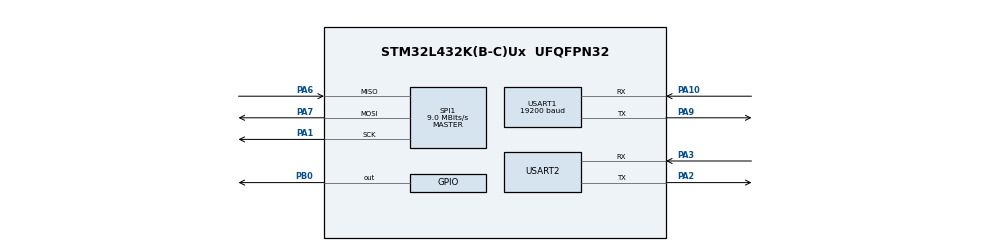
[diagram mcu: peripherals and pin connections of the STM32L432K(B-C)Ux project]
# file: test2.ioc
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FATFS._MAX_SS=4096
FATFS._USE_LFN=1
Mcu.Family=STM32L4
Mcu.Name=STM32L432K(B-C)Ux
Mcu.Package=UFQFPN32
NVIC.PriorityGroup=NVIC_PRIORITYGROUP_4
PA0.Mode=HSE-External-Clock-Source-for-LittleOrca
PA0.Signal=RCC_CK_IN
PA1.Mode=Full_Duplex_Master
PA1.Signal=SPI1_SCK
PA10.Mode=Asynchronous
PA10.Signal=USART1_RX
PA13\ (JTMS-SWDIO).Mode=Serial_Wire
PA13\ (JTMS-SWDIO).Signal=SYS_JTMS-SWDIO
PA14\ (JTCK-SWCLK).Mode=Serial_Wire
PA14\ (JTCK-SWCLK).Signal=SYS_JTCK-SWCLK
PA2.Mode=Asynchronous
PA2.Signal=USART2_TX
PA3.Mode=Asynchronous
PA3.Signal=USART2_RX
PA6.Mode=Full_Duplex_Master
PA6.Signal=SPI1_MISO
PA7.Mode=Full_Duplex_Master
PA7.Signal=SPI1_MOSI
PA9.Mode=Asynchronous
PA9.Signal=USART1_TX
PB0.Signal=GPIO_Output
ProjectManager.HeapSize=0x200
ProjectManager.StackSize=0x400
ProjectManager.TargetToolchain=MDK-ARM V5
RCC.ADCFreq_Value=32000000
RCC.AHBFreq_Value=72000000
RCC.APB1CLKDivider=RCC_HCLK_DIV2
RCC.APB1Freq_Value=36000000
RCC.APB1TimFreq_Value=72000000
RCC.APB2Freq_Value=72000000
RCC.APB2TimFreq_Value=72000000
RCC.CortexFreq_Value=72000000
RCC.HCLKFreq_Value=72000000
RCC.HSE_VALUE=8000000
RCC.HSI48_VALUE=48000000
RCC.HSI_VALUE=16000000
RCC.LSE_VALUE=32768
RCC.MSI_VALUE=4000000
RCC.PLLN=18
RCC.PLLSourceVirtual=RCC_PLLSOURCE_HSE
RCC.SYSCLKFreq_VALUE=72000000
RCC.SYSCLKSource=RCC_SYSCLKSOURCE_PLLCLK
RCC.USBFreq_Value=32000000
RCC.VCOOutputFreq_Value=144000000
SPI1.BaudRatePrescaler=SPI_BAUDRATEPRESCALER_8
SPI1.CalculateBaudRate=9.0 MBits/s
SPI1.Direction=SPI_DIRECTION_2LINES
SPI1.Mode=SPI_MODE_MASTER
SPI1.VirtualType=VM_MASTER
USART1.BaudRate=19200
USART1.VirtualMode-Asynchronous=VM_ASYNC
USART2.VirtualMode-Asynchronous=VM_ASYNC
VP_FATFS_VS_Generic.Mode=User_defined
board=custom

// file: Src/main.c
/* USER CODE BEGIN Header */
/**
  ******************************************************************************
  * @file           : main.c
  * @brief          : Main program body
  ******************************************************************************
  * @attention
  *
  * <h2><center>&copy; Copyright (c) 2020 STMicroelectronics.
  * All rights reserved.</center></h2>
  *
  * This software component is licensed by ST under BSD 3-Clause license,
  * the "License"; You may not use this file except in compliance with the
  * License. You may obtain a copy of the License at:
  *                        opensource.org/licenses/BSD-3-Clause
  *
  ******************************************************************************
  */
/* USER CODE END Header */

#include "main.h"
#include "fatfs.h"

/* USER CODE BEGIN Includes */
#include <stdio.h>
#include <stdlib.h>
#include <ctype.h>
#include <errno.h>
#include <string.h>
/* USER CODE END Includes */

SPI_HandleTypeDef hspi1;
UART_HandleTypeDef huart1;
UART_HandleTypeDef huart2;

void SystemClock_Config(void);
static void MX_GPIO_Init(void);
static void MX_SPI1_Init(void);
static void MX_USART1_UART_Init(void);
static void MX_USART2_UART_Init(void);

/* USER CODE BEGIN 0 */
FATFS fs;  // file system
FIL fil; // File
FILINFO fno;
FRESULT fresult;  // result
UINT br, bw;  // File read/write count
char buffer[1024];
char temp[1024];
char direction[1024];
int c;
int volatile turn = 0;
int volatile start;
int volatile Number_Of_States=0;
int volatile Number_Of_States_2=0;
int volatile Number_Of_Rotations=0;
int volatile Number_Of_Rotations_2=0;
int volatile previous_state;
int volatile previous_state_2;

/**** capacity related *****/
FATFS *pfs;
DWORD fre_clust;
uint32_t total, free_space;

void send_uart(char *string){
	uint8_t len = strlen(string);
	HAL_UART_Transmit(&huart2, (uint8_t *) string, len, HAL_MAX_DELAY);
}

int bufsize(char *buf){
	int i = 0;
	while (*buf++ != '\0') i++;
	return i;
}

void bufclear(void){
	for(int i = 0; i < 1024; i++){
		buffer[i] = '\0';
	}
}

/* USER CODE END 0 */

int main(void)
{

  /* MCU Configuration--------------------------------------------------------*/

  /* Reset of all peripherals, Initializes the Flash interface and the Systick. */
  HAL_Init();

  /* Configure the system clock */
  SystemClock_Config();

  /* Initialize all configured peripherals */
  MX_GPIO_Init();
  MX_SPI1_Init();
  MX_FATFS_Init();
	MX_USART1_UART_Init();
	MX_USART2_UART_Init();
  /* USER CODE BEGIN 2 */

	previous_state=HAL_GPIO_ReadPin(GPIOA,GPIO_PIN_11);
	int flag=1;
	int temp_directions_count=0;
	float volatile distance=0.0;

	HAL_GPIO_WritePin(GPIOB, GPIO_PIN_7, GPIO_PIN_RESET);

	previous_state=HAL_GPIO_ReadPin(GPIOA,GPIO_PIN_11);
	previous_state_2=HAL_GPIO_ReadPin(GPIOA,GPIO_PIN_0);

  fresult = f_mount(&fs, "/", 1);

	/* Check free space */
	f_getfree("", &fre_clust, &pfs);

	total = (uint32_t)((pfs->n_fatent - 2) * pfs->csize * 0.5);
	sprintf (buffer, "SD CARD Total Size: \t%lu\n\r",(unsigned long) total);
	send_uart(buffer);
	bufclear();

	free_space = (uint32_t)(fre_clust * pfs->csize * 0.5);
	sprintf (buffer, "SD CARD free space: \t%lu\n\r",(unsigned long) free_space);
	send_uart(buffer);
	bufclear();

	if(free_space < 100){
		send_uart("WARNING: not enough free space!\n\n\r");
	}

	fresult = f_open(&fil, "FILE1.TXT", FA_OPEN_ALWAYS | FA_READ | FA_WRITE);
	f_read(&fil, buffer, f_size(&fil), &br);
	send_uart(buffer);
	f_close(&fil);
	HAL_GPIO_WritePin(GPIOB, GPIO_PIN_7, GPIO_PIN_SET);

	int count = 0;

	for( int i = 0; i < sizeof(buffer); i++){
		if((buffer[i] != ' ') && (buffer[i] != '\n') && (buffer[i] != '\r')){
				temp[count] = buffer[i];
				count++;
		}
	}
	count = 0;

	int num;

	for( int i = 0; i < sizeof(temp); i++){
		if(temp[i] == 'F'){
			sscanf(&temp[i+1], "%d", &num);
			while(num > 0){
				direction[count] = temp[i];
				count++;
				num--;
			}
		}
		else if(temp[i] == 'B'){
			sscanf(&temp[i+1], "%d", &num);
			direction[count] = 'B';
			count++;
			num--;
			while(num > 0){
				direction[count] = 'F';
				count++;
				num--;
			}
		}
		else if(temp[i] == 'L' || temp[i] == 'R'){
			direction[count] = temp[i];
			count++;
		}
	}

	send_uart(direction);
	count = 0;
	turn = 1;
	HAL_GPIO_WritePin(GPIOB, GPIO_PIN_5, GPIO_PIN_SET);
  /* USER CODE END 2 */

  /* Infinite loop */
  /* USER CODE BEGIN WHILE */
  while (1)
  {
		uint8_t wheel[] = {0xC1, 0xC9, 0xC1, 0xC9,0xC0};
		uint8_t speed[] = {64, 32, 0};
		start = HAL_GPIO_ReadPin(GPIOA, GPIO_PIN_8);
		if(flag==1 && direction[temp_directions_count]=='F' && turn == 0 && start == 1)
		{
			HAL_GPIO_WritePin(GPIOB, GPIO_PIN_5, GPIO_PIN_RESET);
			HAL_UART_Transmit(&huart1, &wheel[0], 1, HAL_MAX_DELAY);
			HAL_UART_Transmit(&huart1, &speed[0], 1, HAL_MAX_DELAY);
			HAL_UART_Transmit(&huart1, &wheel[1], 1, HAL_MAX_DELAY);
			HAL_UART_Transmit(&huart1, &speed[0], 1, HAL_MAX_DELAY);
			distance=Number_Of_Rotations*(12.5/100);
			if(distance >= 0.85){
				temp_directions_count++;
				Number_Of_Rotations=0;
				Number_Of_Rotations_2=0;
				turn = 1;
			}
		}
		else if (flag==1 && direction[temp_directions_count]=='L' && turn == 0 && start == 1)
		{
			HAL_UART_Transmit(&huart1, &wheel[0], 1, HAL_MAX_DELAY);
			HAL_UART_Transmit(&huart1, &speed[0], 1, HAL_MAX_DELAY);
			HAL_UART_Transmit(&huart1, &wheel[1], 1, HAL_MAX_DELAY);
			HAL_UART_Transmit(&huart1, &speed[2], 1, HAL_MAX_DELAY);
			distance=Number_Of_Rotations_2*(12.5/100);
			if(distance >= 0.75){
				temp_directions_count++;
				Number_Of_Rotations=0;
				Number_Of_Rotations_2=0;
			}
		}
		else if (flag==1 && direction[temp_directions_count]=='R' && turn == 0 && start == 1)
		{
				HAL_UART_Transmit(&huart1, &wheel[0], 1, HAL_MAX_DELAY);
				HAL_UART_Transmit(&huart1, &speed[2], 1, HAL_MAX_DELAY);
				HAL_UART_Transmit(&huart1, &wheel[1], 1, HAL_MAX_DELAY);
				HAL_UART_Transmit(&huart1, &speed[0], 1, HAL_MAX_DELAY);
				distance=Number_Of_Rotations*(12.5/100);
				if(distance >= .50){
					temp_directions_count++;
					Number_Of_Rotations=0;
					Number_Of_Rotations_2=0;
				}
		}
		else if(turn == 1 && start == 0){
			HAL_GPIO_WritePin(GPIOB, GPIO_PIN_5, GPIO_PIN_SET);
			HAL_UART_Transmit(&huart1, &wheel[0], 1, HAL_MAX_DELAY);
			HAL_UART_Transmit(&huart1, &speed[2], 1, HAL_MAX_DELAY);
			HAL_UART_Transmit(&huart1, &wheel[1], 1, HAL_MAX_DELAY);
			HAL_UART_Transmit(&huart1, &speed[2], 1, HAL_MAX_DELAY);
			turn = 0;
		}
		else{
			HAL_UART_Transmit(&huart1, &wheel[0], 1, HAL_MAX_DELAY);
			HAL_UART_Transmit(&huart1, &speed[2], 1, HAL_MAX_DELAY);
			HAL_UART_Transmit(&huart1, &wheel[1], 1, HAL_MAX_DELAY);
			HAL_UART_Transmit(&huart1, &speed[2], 1, HAL_MAX_DELAY);
		}
    /* USER CODE END WHILE */

  }
}

void SystemClock_Config(void)
{
  RCC_OscInitTypeDef RCC_OscInitStruct = {0};
  RCC_ClkInitTypeDef RCC_ClkInitStruct = {0};

  /** Initializes the CPU, AHB and APB busses clocks
  */
  RCC_OscInitStruct.OscillatorType = RCC_OSCILLATORTYPE_HSE;
  RCC_OscInitStruct.HSEState = RCC_HSE_ON;
  //RCC_OscInitStruct.HSEPredivValue = RCC_HSE_PREDIV_DIV1;
  RCC_OscInitStruct.HSIState = RCC_HSI_ON;
  RCC_OscInitStruct.PLL.PLLState = RCC_PLL_ON;
  RCC_OscInitStruct.PLL.PLLSource = RCC_PLLSOURCE_HSE;
  //RCC_OscInitStruct.PLL.PLLMUL = RCC_PLL_MUL9;
  if (HAL_RCC_OscConfig(&RCC_OscInitStruct) != HAL_OK)
  {
    Error_Handler();
  }
  /** Initializes the CPU, AHB and APB busses clocks
  */
  RCC_ClkInitStruct.ClockType = RCC_CLOCKTYPE_HCLK|RCC_CLOCKTYPE_SYSCLK
                              |RCC_CLOCKTYPE_PCLK1|RCC_CLOCKTYPE_PCLK2;
  RCC_ClkInitStruct.SYSCLKSource = RCC_SYSCLKSOURCE_PLLCLK;
  RCC_ClkInitStruct.AHBCLKDivider = RCC_SYSCLK_DIV1;
  RCC_ClkInitStruct.APB1CLKDivider = RCC_HCLK_DIV2;
  RCC_ClkInitStruct.APB2CLKDivider = RCC_HCLK_DIV1;

  if (HAL_RCC_ClockConfig(&RCC_ClkInitStruct, FLASH_LATENCY_2) != HAL_OK)
  {
    Error_Handler();
  }
}

static void MX_SPI1_Init(void)
{

  /* SPI1 parameter configuration*/
  hspi1.Instance = SPI1;
  hspi1.Init.Mode = SPI_MODE_MASTER;
  hspi1.Init.Direction = SPI_DIRECTION_2LINES;
  hspi1.Init.DataSize = SPI_DATASIZE_8BIT;
  hspi1.Init.CLKPolarity = SPI_POLARITY_LOW;
  hspi1.Init.CLKPhase = SPI_PHASE_1EDGE;
  hspi1.Init.NSS = SPI_NSS_SOFT;
  hspi1.Init.BaudRatePrescaler = SPI_BAUDRATEPRESCALER_32;
  hspi1.Init.FirstBit = SPI_FIRSTBIT_MSB;
  hspi1.Init.TIMode = SPI_TIMODE_DISABLE;
  hspi1.Init.CRCCalculation = SPI_CRCCALCULATION_DISABLE;
  hspi1.Init.CRCPolynomial = 10;
  if (HAL_SPI_Init(&hspi1) != HAL_OK)
  {
    Error_Handler();
  }

}

static void MX_USART1_UART_Init(void)
{

  huart1.Instance = USART1;
  huart1.Init.BaudRate = 19200;
  huart1.Init.WordLength = UART_WORDLENGTH_8B;
  huart1.Init.StopBits = UART_STOPBITS_1;
  huart1.Init.Parity = UART_PARITY_NONE;
  huart1.Init.Mode = UART_MODE_TX_RX;
  huart1.Init.HwFlowCtl = UART_HWCONTROL_NONE;
  huart1.Init.OverSampling = UART_OVERSAMPLING_16;
  huart1.Init.OneBitSampling = UART_ONE_BIT_SAMPLE_DISABLE;
  huart1.AdvancedInit.AdvFeatureInit = UART_ADVFEATURE_NO_INIT;
  if (HAL_UART_Init(&huart1) != HAL_OK)
  {
    Error_Handler();
  }

}

static void MX_USART2_UART_Init(void)
{

  huart2.Instance = USART2;
  huart2.Init.BaudRate = 9600;
  huart2.Init.WordLength = UART_WORDLENGTH_8B;
  huart2.Init.StopBits = UART_STOPBITS_1;
  huart2.Init.Parity = UART_PARITY_NONE;
  huart2.Init.Mode = UART_MODE_TX_RX;
  huart2.Init.HwFlowCtl = UART_HWCONTROL_NONE;
  huart2.Init.OverSampling = UART_OVERSAMPLING_16;
  huart2.Init.OneBitSampling = UART_ONE_BIT_SAMPLE_DISABLE;
  huart2.AdvancedInit.AdvFeatureInit = UART_ADVFEATURE_NO_INIT;
  if (HAL_UART_Init(&huart2) != HAL_OK)
  {
    Error_Handler();
  }

}

static void MX_GPIO_Init(void)
{
  GPIO_InitTypeDef GPIO_InitStruct = {0};

  /* GPIO Ports Clock Enable */
  //__HAL_RCC_GPIOD_CLK_ENABLE();
  __HAL_RCC_GPIOA_CLK_ENABLE();
  __HAL_RCC_GPIOB_CLK_ENABLE();

  /*Configure GPIO pin Output Level */
  HAL_GPIO_WritePin(GPIOB, GPIO_PIN_0|GPIO_PIN_7, GPIO_PIN_SET);
	  /*Configure GPIO pin Output Level */
  HAL_GPIO_WritePin(GPIOA, GPIO_PIN_1|GPIO_PIN_4, GPIO_PIN_RESET);
  /*Configure GPIO pin Output Level */
  HAL_GPIO_WritePin(GPIOB, GPIO_PIN_5|GPIO_PIN_3, GPIO_PIN_RESET);

  /*Configure GPIO pin : PB0 */
  GPIO_InitStruct.Pin = GPIO_PIN_0|GPIO_PIN_7;
  GPIO_InitStruct.Mode = GPIO_MODE_OUTPUT_PP;
  GPIO_InitStruct.Pull = GPIO_NOPULL;
  GPIO_InitStruct.Speed = GPIO_SPEED_FREQ_LOW;
  HAL_GPIO_Init(GPIOB, &GPIO_InitStruct);
	  /*Configure GPIO pins : PA1 PA4 */
  GPIO_InitStruct.Pin = GPIO_PIN_1|GPIO_PIN_4;
  GPIO_InitStruct.Mode = GPIO_MODE_OUTPUT_PP;
  GPIO_InitStruct.Pull = GPIO_NOPULL;
  GPIO_InitStruct.Speed = GPIO_SPEED_FREQ_LOW;
  HAL_GPIO_Init(GPIOA, &GPIO_InitStruct);

  /*Configure GPIO pin : PA11 */
  GPIO_InitStruct.Pin = GPIO_PIN_8;
  GPIO_InitStruct.Mode = GPIO_MODE_INPUT;
  GPIO_InitStruct.Pull = GPIO_NOPULL;
  HAL_GPIO_Init(GPIOA, &GPIO_InitStruct);

  /*Configure GPIO pin : PB5 */
  GPIO_InitStruct.Pin = GPIO_PIN_5;
  GPIO_InitStruct.Mode = GPIO_MODE_OUTPUT_PP;
  GPIO_InitStruct.Pull = GPIO_NOPULL;
  GPIO_InitStruct.Speed = GPIO_SPEED_FREQ_LOW;
  HAL_GPIO_Init(GPIOB, &GPIO_InitStruct);

	/*Configure GPIO pins : PA0 PA11 */
  GPIO_InitStruct.Pin = GPIO_PIN_0|GPIO_PIN_11;
  GPIO_InitStruct.Mode = GPIO_MODE_INPUT;
  GPIO_InitStruct.Pull = GPIO_NOPULL;
  HAL_GPIO_Init(GPIOA, &GPIO_InitStruct);

  /*Configure GPIO pin : PB3 */
  GPIO_InitStruct.Pin = GPIO_PIN_3;
  GPIO_InitStruct.Mode = GPIO_MODE_OUTPUT_PP;
  GPIO_InitStruct.Pull = GPIO_NOPULL;
  GPIO_InitStruct.Speed = GPIO_SPEED_FREQ_LOW;
  HAL_GPIO_Init(GPIOB, &GPIO_InitStruct);

}

void Error_Handler(void)
{
}

/************************ (C) COPYRIGHT STMicroelectronics *****END OF FILE****/
